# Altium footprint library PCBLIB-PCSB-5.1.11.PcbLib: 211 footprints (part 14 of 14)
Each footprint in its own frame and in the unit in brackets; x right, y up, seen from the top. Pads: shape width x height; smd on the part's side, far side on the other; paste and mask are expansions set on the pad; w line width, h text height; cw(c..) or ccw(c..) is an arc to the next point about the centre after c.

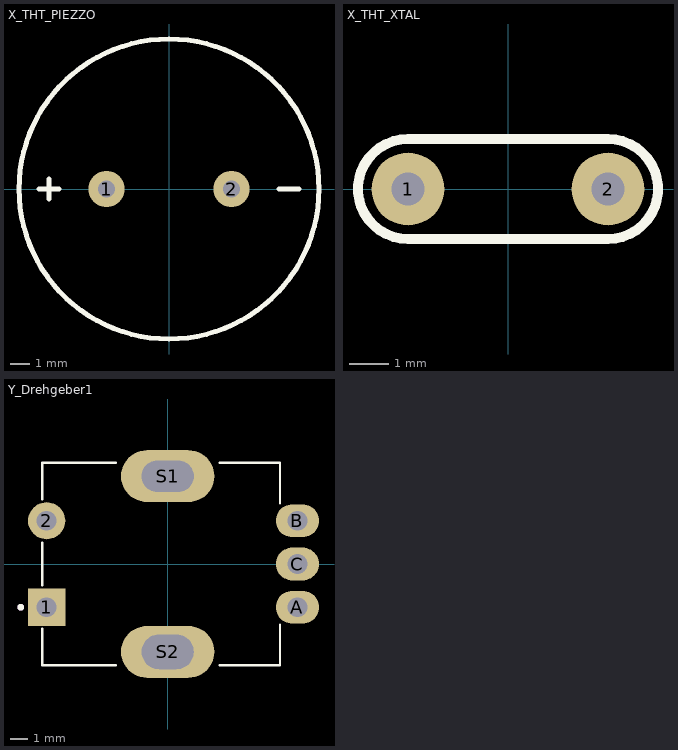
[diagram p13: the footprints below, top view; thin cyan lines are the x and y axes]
## X_THT_PIEZZO [mm] "LB-2024-04-18"
pads (2):
  round 1.85 hole 0.85: 1(-3.175,0) 2(3.175,0)
Top Overlay:
  circle w0.254: c0,0 r7.62
  lines w0.254: -6.604,0 -5.588,0 ; -6.096,-0.508 -6.096,0.508 ; 5.588,0 6.604,0

## X_THT_XTAL [mm] "LB-2024-04-17"
pads (2):
  round 1.85 hole 0.85: 1(-2.54,0) 2(2.54,0)
Top Overlay:
  lines w0.254: -2.54,-1.27 cw(c-2.54,0) -2.54,1.27 2.54,1.27 cw(c2.54,0) 2.54,-1.27 -2.54,-1.27

## Y_Drehgeber1 [mm] "LB-2024-04-19"
pads (7):
  rect 2.15x2.15 hole 1.15: 1(-7,-2.5)
  round 2.15 hole 1.15: 2(-7,2.5)
  oval 2.5x1.9 hole 1.15: A(7.5,-2.5) B(7.5,2.5) C(7.5,0)
  oval 5.4x3 hole 1.8 slot 3 at 0 deg: S1(0,5.08)
  oval 5.4x3 hole 2 slot 3 at 0 deg: S2(0,-5.08)
Top Overlay:
  circle w0.2: c-8.5,-2.5 r0.1
  lines w0.127: -7.25,-3.75 -7.25,-5.85 -3,-5.85 ; -7.25,-1.25 -7.25,1.25 ; -7.25,3.75 -7.25,5.85 -3,5.85 ; 3,-5.85 6.5,-5.85 6.5,-3.5 ; 3,5.85 6.5,5.85 6.5,3.5
Mechanical 13:
  circle w0.2: c-8.5,-2.5 r0.1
